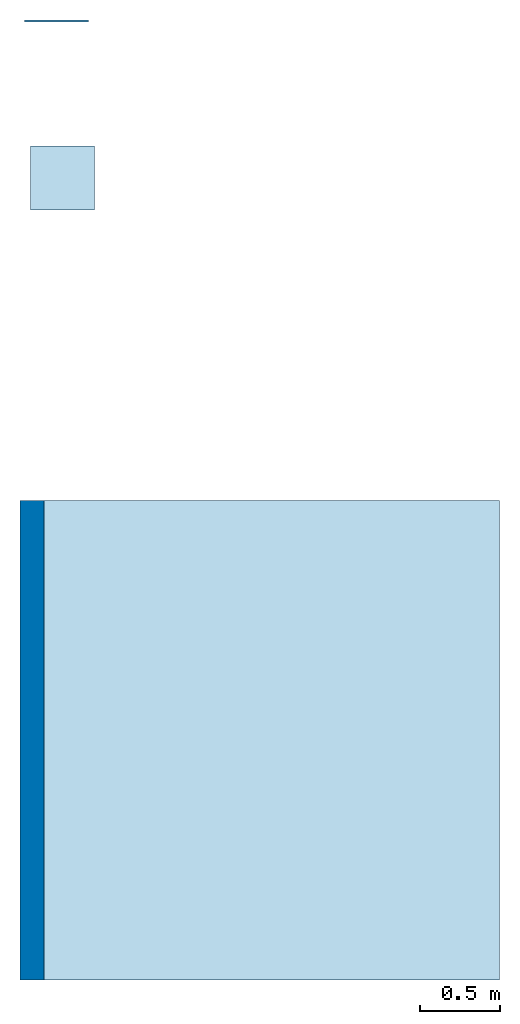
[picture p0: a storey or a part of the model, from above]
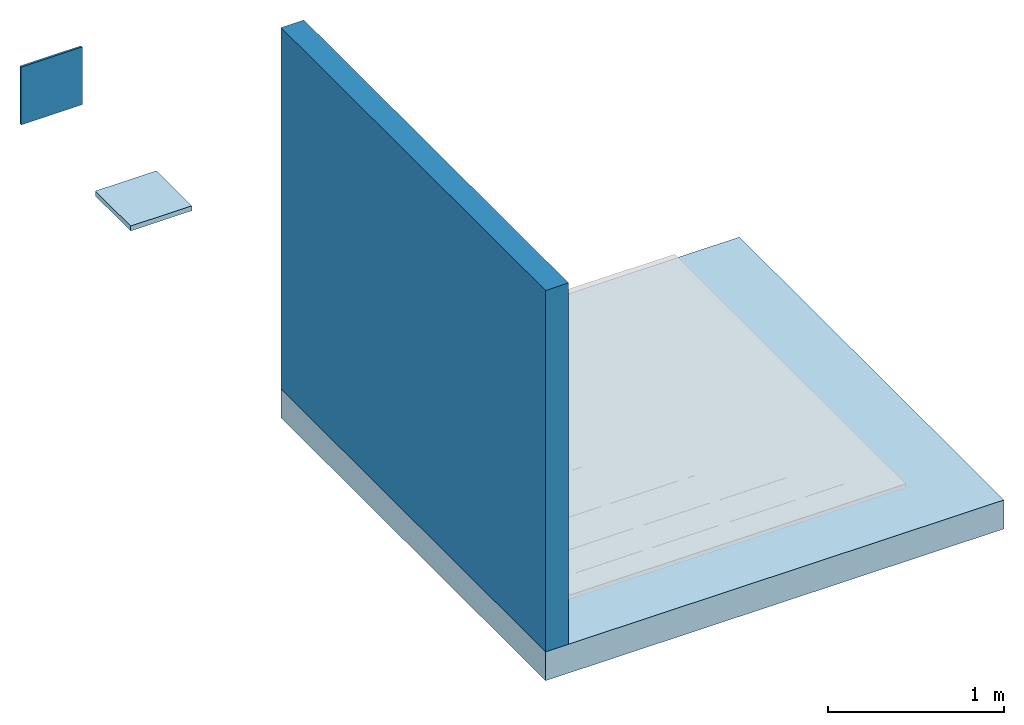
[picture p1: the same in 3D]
Properties of the parts of a building model (IFC2X3)

# File
Description: ViewDefinition [CoordinationView_V2.0], RevitIdentifiers [VersionGUID: 5ec4efa4-79ac-4960-a8b9-bd8d55ba5293, NumberOfSaves: 15], CoordinateReference [CoordinateBase: Coordenadas compartilhadas]
File name: 0001
Time: 2024-04-24T15:58:49
Written by: ODA IFC SDK 22.8
Made in: 22.1.50.17 - Exporter 22.6.2.0 - IU alternativa 22.6.2.0

# IfcProject, 0001
LongName: Vagas de Veículos elevadas - Vulkem; Phase: Status do projeto

# IfcSite, Default
RefLatitude: 42, 21, 31, 181944; RefLongitude: -71, -3, -24, -263304; RefElevation: 0 m

# IfcBuilding
Pset_BuildingCommon - NumberOfStoreys: 1; IsLandmarked: no

# IfcBuildingStorey: Nível:Cabeça de 8 mm, ARQ Térreo
LongName: ARQ Térreo; Elevation: -0.0025238 m

# IfcBuildingElementProxy: IMPER:IMPER:433934, IMPER:IMPER:433934:IMPER:433934 : IMPER:IMPER:433934:291594
In: ARQ Térreo
Type - Material: #argamassa, #Vulkem 346, #Vulkem 345, #Vulkem 350NF, #Selante, #Vulkem 171 Primer
Type - Pset_BuildingElementProxyCommon - Reference: IMPER
Type - Pset_QuantityTakeOff - Reference: IMPER
Type - Pset_ProvisionForVoid - Width: 0.952886 m; Height: 0.00103887 m; Depth: 2.62 m
Pset_BuildingElementProxyCommon - sets with these values: 2

# IfcSlab: Piso:IMPH_VLK ruas, Piso:IMPH_VLK ruas:293670
In: ARQ Térreo
Type - PredefinedType: FLOOR; Material: #Vulkem 346 0.001 m, #Vulkem 345 0.001 m, #Vulkem 350NF 0.001 m, #Vulkem 171 Primer 0.001 m, #argamassa 0.03 m
Type - Pset_SlabCommon - IsExternal: no
Pset_QuantityTakeOff - Reference: IMPH_VLK ruas; sets with these values: 2
Pset_SlabCommon - LoadBearing: no; PitchAngle: 0 deg; Reference: IMPH_VLK ruas

# IfcSlab: Piso:Piso:LAJE CONCRETO, Piso:Piso:LAJE CONCRETO:293651
In: ARQ Térreo
Type - PredefinedType: FLOOR; Material: #concreto 0.2 m
Type - Pset_SlabCommon - IsExternal: no
Pset_QuantityTakeOff - Reference: Piso:LAJE CONCRETO; sets with these values: 2
Pset_SlabCommon - Reference: Piso:LAJE CONCRETO; LoadBearing: no; PitchAngle: 0 deg

# IfcWallStandardCase: Parede básica:IMPV_VLK ruas, Parede básica:IMPV_VPECO:459587
In: ARQ Térreo
Type - PredefinedType: STANDARD; Material: #Vulkem 346 0.001 m, #Vulkem 345 0.001 m, #Vulkem 350NF 0.001 m, #Vulkem 171 Primer 0.001 m, #argamassa 0.01 m
Type - Pset_WallCommon - IsExternal: yes; ThermalTransmittance: 510 kg/K/s3
Pset_QuantityTakeOff - Reference: IMPV_VPECO; sets with these values: 2
Pset_WallCommon - LoadBearing: no; ExtendToStructure: no; Reference: IMPV_VPECO

# IfcWallStandardCase: Parede básica:Parede básica:Parede Concreto, Parede básica:Parede Concreto:395312
In: ARQ Térreo
Type - PredefinedType: STANDARD; Material: #concreto 0.15 m
Type - Pset_WallCommon - IsExternal: yes; ThermalTransmittance: 6.97333 kg/K/s3
Pset_QuantityTakeOff - Reference: Parede Concreto; sets with these values: 2
Pset_WallCommon - LoadBearing: no; Reference: Parede Concreto; ExtendToStructure: no
